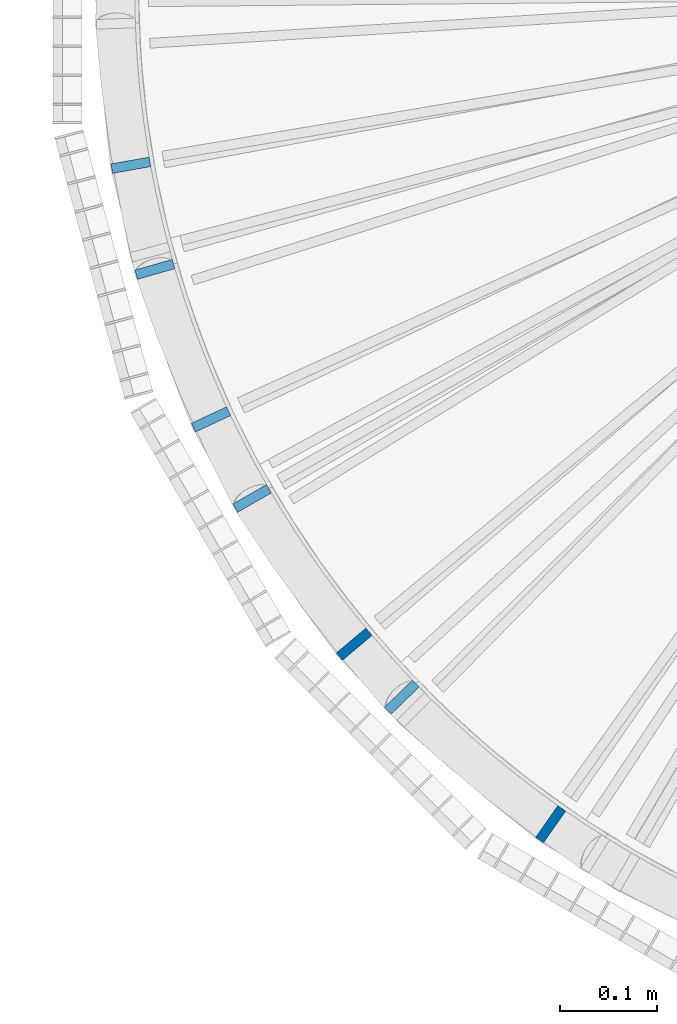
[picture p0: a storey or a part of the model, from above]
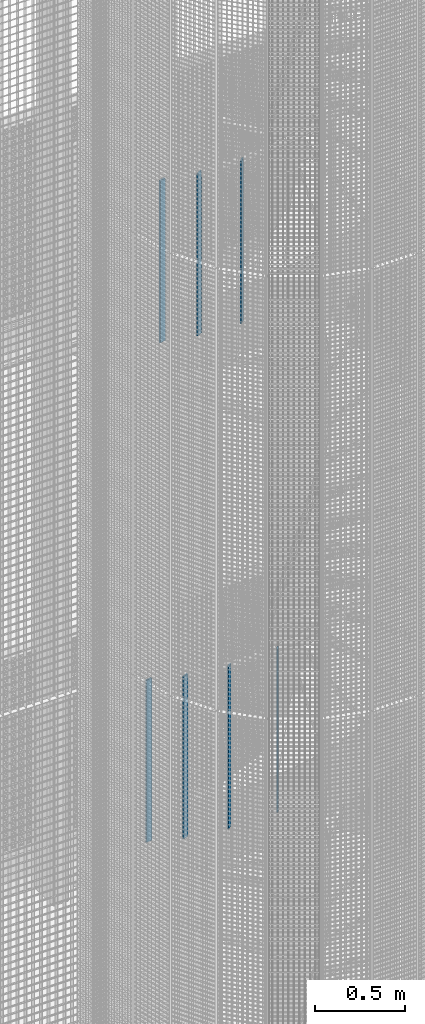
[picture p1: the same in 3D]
Properties of the parts of a building model (IFC2X3)

# File
Description: ViewDefinition[CoordinationView_V2.0], Option [GridExport:On], Option [Assemblies:On], Option [Bolts:Off], Option [Rebars:Off], Option [PourObjects:Off], Option [Welds:Off], Option [SurfaceTreatments:On], Option [LocationBy:0], Option [ViewColors:Off], Option [SectionedSpine:Off], Option [PropertySets:On], Option [Export all:Off]
File name: DCE4-CHM-LILLE-CNRS-IBL-251030.ifc
Time: 2025-10-30T11:35:05
Author: PROJEX0\sthumerel
Organization: Structural Designer
Written by: IFC Parser Version: 3.14.0
Made in: Tekla Structures 2024 Service Pack 10, IFC Export Version: 4.0.0.0 Sep 4 2025

# IfcBuildingStorey, Undefined
In: Undefined
Elevation: 0 mm

# IfcBeam: IPE240 (32)
In: Undefined
Description: IPE240; Material: STEEL/S235JR

# IfcBeam: PL10*40 (459)
In: Undefined
Description: PL10*40; Material: STEEL/S235JR
Name
458 x RAIDISSEUR
MONTANT

# IfcBeam: PL2*10 (26958)
In: Undefined
Description: PL2*10; Material: STEEL/S235JR

# IfcBeam: PLT4*450 (12)
In: Undefined
Description: PLT4*450; Material: STEEL/S235JR

# IfcBeam: ROND-14MM (10)
In: Undefined
Description: ROND-14MM; Material: STEEL/S235JR

# IfcBeam: TUBE-42.4*3.2 (12)
In: Undefined
Description: TUBE-42.4*3.2; Material: STEEL/S235JR

# IfcBeam: TUBE-60.3*5 (16)
In: Undefined
Description: TUBE-60.3*5; Material: STEEL/S275JR

# IfcBeam: TUBE-R-60*40*3 (32)
In: Undefined
Description: TUBE-R-60*40*3; Material: STEEL/S235JR

# IfcBeam: UPE240 (8)
In: Undefined
Description: UPE240; Material: STEEL/S235JR

# IfcBeam: UPE270 (8)
In: Undefined
Description: UPE270; Material: STEEL/S235JR

# IfcBeam: UPE300 (8)
In: Undefined
Description: UPE300; Material: STEEL/S275JR

# IfcBeam: UPF-200*80*4 (8)
In: Undefined
Description: UPF-200*80*4; Material: STEEL/S275JR

# IfcColumn: PL10*40 (237)
In: Undefined
Description: PL10*40; Material: STEEL/S235JR

# IfcColumn: TUBE-273*6.3 (8)
In: Undefined
Description: TUBE-273*6.3; Material: STEEL/S235JR

# IfcColumn: TUBE-R-200*100*4 (12)
In: Undefined
Description: TUBE-R-200*100*4; Material: STEEL/S235JR

# IfcColumn: TUBE-R-40*20*2 (80)
In: Undefined
Description: TUBE-R-40*20*2; Material: Undefined/FE510D

# IfcColumn: TUBE-R-60*40*3 (32)
In: Undefined
Description: TUBE-R-60*40*3; Material: Undefined/FE510D

# IfcCovering: Galvanisé (275)
In: Undefined
Material: Undefined/Undefined

# IfcMember: ROND-14MM (220)
In: Undefined
Description: ROND-14MM; Material: STEEL/S235JR

# IfcMember: TUBE-42.4*3.2 (220)
In: Undefined
Description: TUBE-42.4*3.2; Material: STEEL/S235JR

# IfcPlate: PL2*30 (3451)
In: Undefined
Description: PL2*30; Material: STEEL/S235JR
Name
2386 x BARRE PORTEUSE
1065 x BORDURE

# IfcPlate: PL2*50 (704)
In: Undefined
Description: PL2*50; Material: STEEL/S235JR
Name
672 x BARRE PORTEUSE
32 x BORDURE

# IfcPlate: PL4*163.8 (2)
In: Undefined
Description: PL4*163.8; Material: STEEL/S235JR

# IfcPlate: PL4*178.9 (2)
In: Undefined
Description: PL4*178.9; Material: STEEL/S235JR

# IfcPlate: PL4*501.7 (2)
In: Undefined
Description: PL4*501.7; Material: STEEL/S235JR

# IfcPlate: PL4*530 (228)
In: Undefined
Description: PL4*530; Material: STEEL/S235JR

# IfcPlate: PL4*933.2 (2)
In: Undefined
Description: PL4*933.2; Material: STEEL/S235JR

# IfcPlate: PLT4*3000 (218)
In: Undefined
Description: PLT4*3000; Material: STEEL/S235JR

# IfcSlab: 315*2950 (8)
In: Undefined
Description: 315*2950; Material: CONCRETE/BETON

# IfcWall: 200*385 (8)
In: Undefined
Description: 200*385; Material: CONCRETE/BETON

# IfcWall: 200*620 (8)
In: Undefined
Description: 200*620; Material: CONCRETE/BETON
